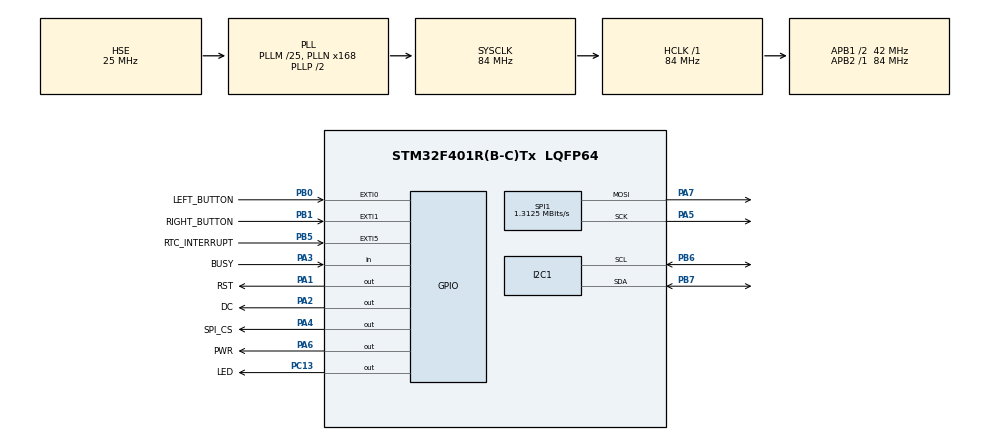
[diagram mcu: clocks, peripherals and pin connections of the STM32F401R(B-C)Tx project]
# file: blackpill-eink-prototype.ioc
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Mcu.Family=STM32F4
Mcu.Name=STM32F401R(B-C)Tx
Mcu.Package=LQFP64
NVIC.EXTI0_IRQn=true\:0\:0\:false\:false\:true\:true\:true\:true
NVIC.EXTI1_IRQn=true\:0\:0\:false\:false\:true\:true\:true\:true
NVIC.EXTI9_5_IRQn=true\:0\:0\:false\:false\:true\:true\:true\:true
NVIC.PriorityGroup=NVIC_PRIORITYGROUP_4
PA1.GPIO_Label=RST
PA1.Signal=GPIO_Output
PA13.Mode=Serial_Wire
PA13.Signal=SYS_JTMS-SWDIO
PA14.Mode=Serial_Wire
PA14.Signal=SYS_JTCK-SWCLK
PA2.GPIO_Label=DC
PA2.Signal=GPIO_Output
PA3.GPIO_Label=BUSY
PA3.Signal=GPIO_Input
PA4.GPIO_Label=SPI_CS
PA4.Signal=GPIO_Output
PA5.Mode=TX_Only_Simplex_Unidirect_Master
PA5.Signal=SPI1_SCK
PA6.GPIO_Label=PWR
PA6.Signal=GPIO_Output
PA7.Mode=TX_Only_Simplex_Unidirect_Master
PA7.Signal=SPI1_MOSI
PB0.GPIO_Label=LEFT_BUTTON
PB0.GPIO_ModeDefaultEXTI=GPIO_MODE_IT_FALLING
PB0.GPIO_PuPd=GPIO_PULLUP
PB0.Signal=GPXTI0
PB1.GPIO_Label=RIGHT_BUTTON
PB1.GPIO_ModeDefaultEXTI=GPIO_MODE_IT_FALLING
PB1.GPIO_PuPd=GPIO_PULLUP
PB1.Signal=GPXTI1
PB5.GPIO_Label=RTC_INTERRUPT
PB5.GPIO_ModeDefaultEXTI=GPIO_MODE_IT_FALLING
PB5.GPIO_PuPd=GPIO_PULLUP
PB5.Signal=GPXTI5
PB6.GPIO_Pu=GPIO_PULLUP
PB6.Mode=I2C
PB6.Signal=I2C1_SCL
PB7.GPIO_Pu=GPIO_PULLUP
PB7.Mode=I2C
PB7.Signal=I2C1_SDA
PC13-ANTI_TAMP.GPIO_Label=LED
PC13-ANTI_TAMP.PinState=GPIO_PIN_SET
PC13-ANTI_TAMP.Signal=GPIO_Output
PH0\ -\ OSC_IN.Mode=HSE-External-Oscillator
PH0\ -\ OSC_IN.Signal=RCC_OSC_IN
PH1\ -\ OSC_OUT.Mode=HSE-External-Oscillator
PH1\ -\ OSC_OUT.Signal=RCC_OSC_OUT
ProjectManager.HeapSize=0x200
ProjectManager.StackSize=0x400
ProjectManager.TargetToolchain=STM32CubeIDE
RCC.48MHZClocksFreq_Value=42000000
RCC.AHBFreq_Value=84000000
RCC.APB1CLKDivider=RCC_HCLK_DIV2
RCC.APB1Freq_Value=42000000
RCC.APB1TimFreq_Value=84000000
RCC.APB2Freq_Value=84000000
RCC.APB2TimFreq_Value=84000000
RCC.CortexFreq_Value=84000000
RCC.HCLKFreq_Value=84000000
RCC.HSE_VALUE=25000000
RCC.HSI_VALUE=16000000
RCC.LSE_VALUE=32768
RCC.PLLM=25
RCC.PLLN=168
RCC.PLLSourceVirtual=RCC_PLLSOURCE_HSE
RCC.SYSCLKFreq_VALUE=84000000
RCC.SYSCLKSource=RCC_SYSCLKSOURCE_PLLCLK
RCC.VCOOutputFreq_Value=168000000
SPI1.BaudRatePrescaler=SPI_BAUDRATEPRESCALER_64
SPI1.CalculateBaudRate=1.3125 MBits/s
SPI1.Direction=SPI_DIRECTION_2LINES
SPI1.Mode=SPI_MODE_MASTER
SPI1.VirtualType=VM_MASTER
board=custom

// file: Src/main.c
/* USER CODE BEGIN Header */
/**
  ******************************************************************************
  * @file           : main.c
  * @brief          : Main program body
  ******************************************************************************
  * @attention
  *
  * Copyright (c) 2026 STMicroelectronics.
  * All rights reserved.
  *
  * This software is licensed under terms that can be found in the LICENSE file
  * in the root directory of this software component.
  * If no LICENSE file comes with this software, it is provided AS-IS.
  *
  ******************************************************************************
  */
/* USER CODE END Header */
#include "main.h"

/* USER CODE BEGIN Includes */
#include "ds_3231.h"
#include "UI.h"
/* USER CODE END Includes */

I2C_HandleTypeDef hi2c1;

SPI_HandleTypeDef hspi1;

void SystemClock_Config(void);
static void MX_GPIO_Init(void);
static void MX_I2C1_Init(void);
static void MX_SPI1_Init(void);

int main(void)
{

  /* MCU Configuration--------------------------------------------------------*/

  /* Reset of all peripherals, Initializes the Flash interface and the Systick. */
  HAL_Init();

  /* Configure the system clock */
  SystemClock_Config();

  /* Initialize all configured peripherals */
  MX_GPIO_Init();
  MX_I2C1_Init();
  MX_SPI1_Init();
  /* USER CODE BEGIN 2 */
  RTC_handle_interrupt(&hi2c1);
  draw_UI();
  /* USER CODE END 2 */

  /* Infinite loop */
  /* USER CODE BEGIN WHILE */
  while (1)
  {
	  HAL_Delay(1000);
    /* USER CODE END WHILE */

  }
}

void SystemClock_Config(void)
{
  RCC_OscInitTypeDef RCC_OscInitStruct = {0};
  RCC_ClkInitTypeDef RCC_ClkInitStruct = {0};

  /** Configure the main internal regulator output voltage
  */
  __HAL_RCC_PWR_CLK_ENABLE();
  __HAL_PWR_VOLTAGESCALING_CONFIG(PWR_REGULATOR_VOLTAGE_SCALE2);

  /** Initializes the RCC Oscillators according to the specified parameters
  * in the RCC_OscInitTypeDef structure.
  */
  RCC_OscInitStruct.OscillatorType = RCC_OSCILLATORTYPE_HSE;
  RCC_OscInitStruct.HSEState = RCC_HSE_ON;
  RCC_OscInitStruct.PLL.PLLState = RCC_PLL_ON;
  RCC_OscInitStruct.PLL.PLLSource = RCC_PLLSOURCE_HSE;
  RCC_OscInitStruct.PLL.PLLM = 25;
  RCC_OscInitStruct.PLL.PLLN = 168;
  RCC_OscInitStruct.PLL.PLLP = RCC_PLLP_DIV2;
  RCC_OscInitStruct.PLL.PLLQ = 4;
  if (HAL_RCC_OscConfig(&RCC_OscInitStruct) != HAL_OK)
  {
    Error_Handler();
  }

  /** Initializes the CPU, AHB and APB buses clocks
  */
  RCC_ClkInitStruct.ClockType = RCC_CLOCKTYPE_HCLK|RCC_CLOCKTYPE_SYSCLK
                              |RCC_CLOCKTYPE_PCLK1|RCC_CLOCKTYPE_PCLK2;
  RCC_ClkInitStruct.SYSCLKSource = RCC_SYSCLKSOURCE_PLLCLK;
  RCC_ClkInitStruct.AHBCLKDivider = RCC_SYSCLK_DIV1;
  RCC_ClkInitStruct.APB1CLKDivider = RCC_HCLK_DIV2;
  RCC_ClkInitStruct.APB2CLKDivider = RCC_HCLK_DIV1;

  if (HAL_RCC_ClockConfig(&RCC_ClkInitStruct, FLASH_LATENCY_2) != HAL_OK)
  {
    Error_Handler();
  }
}

static void MX_I2C1_Init(void)
{

  hi2c1.Instance = I2C1;
  hi2c1.Init.ClockSpeed = 100000;
  hi2c1.Init.DutyCycle = I2C_DUTYCYCLE_2;
  hi2c1.Init.OwnAddress1 = 0;
  hi2c1.Init.AddressingMode = I2C_ADDRESSINGMODE_7BIT;
  hi2c1.Init.DualAddressMode = I2C_DUALADDRESS_DISABLE;
  hi2c1.Init.OwnAddress2 = 0;
  hi2c1.Init.GeneralCallMode = I2C_GENERALCALL_DISABLE;
  hi2c1.Init.NoStretchMode = I2C_NOSTRETCH_DISABLE;
  if (HAL_I2C_Init(&hi2c1) != HAL_OK)
  {
    Error_Handler();
  }

}

static void MX_SPI1_Init(void)
{

  /* SPI1 parameter configuration*/
  hspi1.Instance = SPI1;
  hspi1.Init.Mode = SPI_MODE_MASTER;
  hspi1.Init.Direction = SPI_DIRECTION_2LINES;
  hspi1.Init.DataSize = SPI_DATASIZE_8BIT;
  hspi1.Init.CLKPolarity = SPI_POLARITY_LOW;
  hspi1.Init.CLKPhase = SPI_PHASE_1EDGE;
  hspi1.Init.NSS = SPI_NSS_SOFT;
  hspi1.Init.BaudRatePrescaler = SPI_BAUDRATEPRESCALER_64;
  hspi1.Init.FirstBit = SPI_FIRSTBIT_MSB;
  hspi1.Init.TIMode = SPI_TIMODE_DISABLE;
  hspi1.Init.CRCCalculation = SPI_CRCCALCULATION_DISABLE;
  hspi1.Init.CRCPolynomial = 10;
  if (HAL_SPI_Init(&hspi1) != HAL_OK)
  {
    Error_Handler();
  }

}

static void MX_GPIO_Init(void)
{
  GPIO_InitTypeDef GPIO_InitStruct = {0};

  /* GPIO Ports Clock Enable */
  __HAL_RCC_GPIOC_CLK_ENABLE();
  __HAL_RCC_GPIOH_CLK_ENABLE();
  __HAL_RCC_GPIOA_CLK_ENABLE();
  __HAL_RCC_GPIOB_CLK_ENABLE();

  /*Configure GPIO pin Output Level */
  HAL_GPIO_WritePin(LED_GPIO_Port, LED_Pin, GPIO_PIN_SET);

  /*Configure GPIO pin Output Level */
  HAL_GPIO_WritePin(GPIOA, RST_Pin|DC_Pin|SPI_CS_Pin|PWR_Pin, GPIO_PIN_RESET);

  /*Configure GPIO pin : LED_Pin */
  GPIO_InitStruct.Pin = LED_Pin;
  GPIO_InitStruct.Mode = GPIO_MODE_OUTPUT_PP;
  GPIO_InitStruct.Pull = GPIO_NOPULL;
  GPIO_InitStruct.Speed = GPIO_SPEED_FREQ_LOW;
  HAL_GPIO_Init(LED_GPIO_Port, &GPIO_InitStruct);

  /*Configure GPIO pins : RST_Pin DC_Pin SPI_CS_Pin PWR_Pin */
  GPIO_InitStruct.Pin = RST_Pin|DC_Pin|SPI_CS_Pin|PWR_Pin;
  GPIO_InitStruct.Mode = GPIO_MODE_OUTPUT_PP;
  GPIO_InitStruct.Pull = GPIO_NOPULL;
  GPIO_InitStruct.Speed = GPIO_SPEED_FREQ_LOW;
  HAL_GPIO_Init(GPIOA, &GPIO_InitStruct);

  /*Configure GPIO pin : BUSY_Pin */
  GPIO_InitStruct.Pin = BUSY_Pin;
  GPIO_InitStruct.Mode = GPIO_MODE_INPUT;
  GPIO_InitStruct.Pull = GPIO_NOPULL;
  HAL_GPIO_Init(BUSY_GPIO_Port, &GPIO_InitStruct);

  /*Configure GPIO pins : LEFT_BUTTON_Pin RIGHT_BUTTON_Pin RTC_INTERRUPT_Pin */
  GPIO_InitStruct.Pin = LEFT_BUTTON_Pin|RIGHT_BUTTON_Pin|RTC_INTERRUPT_Pin;
  GPIO_InitStruct.Mode = GPIO_MODE_IT_FALLING;
  GPIO_InitStruct.Pull = GPIO_PULLUP;
  HAL_GPIO_Init(GPIOB, &GPIO_InitStruct);

  /*Configure GPIO pins : SWITCH_LEFT_Pin SWITCH_RIGHT_Pin */
  GPIO_InitStruct.Pin = SWITCH_LEFT_Pin|SWITCH_RIGHT_Pin;
  GPIO_InitStruct.Mode = GPIO_MODE_IT_FALLING;
  GPIO_InitStruct.Pull = GPIO_PULLUP;
  HAL_GPIO_Init(GPIOA, &GPIO_InitStruct);

  /* EXTI interrupt init*/
  HAL_NVIC_SetPriority(EXTI0_IRQn, 1, 0);
  HAL_NVIC_EnableIRQ(EXTI0_IRQn);

  HAL_NVIC_SetPriority(EXTI1_IRQn, 1, 0);
  HAL_NVIC_EnableIRQ(EXTI1_IRQn);

  HAL_NVIC_SetPriority(EXTI9_5_IRQn, 1, 0);
  HAL_NVIC_EnableIRQ(EXTI9_5_IRQn);

}

/* USER CODE BEGIN 4 */
void HAL_GPIO_EXTI_Callback(uint16_t GPIO_Pin){
	if(GPIO_Pin == RTC_INTERRUPT_Pin){
		RTC_handle_interrupt(&hi2c1);
	}else if(GPIO_Pin == LEFT_BUTTON_Pin || GPIO_Pin == RIGHT_BUTTON_Pin){
		HAL_GPIO_TogglePin(LED_GPIO_Port, LED_Pin);
	}else if(GPIO_Pin == SWITCH_LEFT_Pin){
		HAL_GPIO_TogglePin(LED_GPIO_Port, LED_Pin);
		HAL_Delay(250);
		HAL_GPIO_TogglePin(LED_GPIO_Port, LED_Pin);
		HAL_Delay(250);
	}else if(GPIO_Pin == SWITCH_RIGHT_Pin){
		HAL_GPIO_TogglePin(LED_GPIO_Port, LED_Pin);
		HAL_Delay(250);
		HAL_GPIO_TogglePin(LED_GPIO_Port, LED_Pin);
		HAL_Delay(250);
		HAL_GPIO_TogglePin(LED_GPIO_Port, LED_Pin);
		HAL_Delay(250);
		HAL_GPIO_TogglePin(LED_GPIO_Port, LED_Pin);
		HAL_Delay(250);
	}else{
		__NOP();
	}
}
/* USER CODE END 4 */

void Error_Handler(void)
{
  __disable_irq();
  while (1)
  {
  }
}
